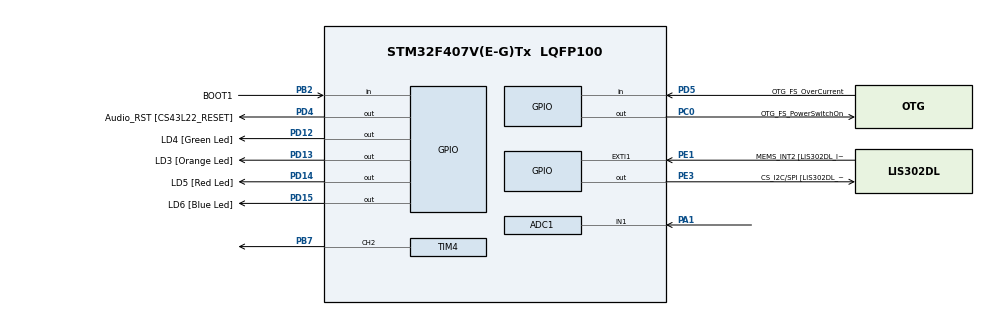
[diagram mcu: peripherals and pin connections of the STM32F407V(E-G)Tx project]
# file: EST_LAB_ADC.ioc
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ADC1.Channel-2\#ChannelRegularConversion=ADC_CHANNEL_1
ADC1.NbrOfConversionFlag=1
ADC1.Rank-2\#ChannelRegularConversion=1
ADC1.SamplingTime-2\#ChannelRegularConversion=ADC_SAMPLETIME_3CYCLES
ADC1.master=1
Mcu.Family=STM32F4
Mcu.Name=STM32F407V(E-G)Tx
Mcu.Package=LQFP100
NVIC.PriorityGroup=NVIC_PRIORITYGROUP_0
PA0-WKUP.Mode=SYS_WakeUp0
PA0-WKUP.Signal=SYS_WKUP
PA1.Signal=ADCx_IN1
PA10.GPIO_Label=OTG_FS_ID
PA10.GPIO_Mode=GPIO_MODE_AF_PP
PA10.GPIO_PuPd=GPIO_NOPULL
PA10.GPIO_Speed=GPIO_SPEED_FREQ_LOW
PA10.Signal=USB_OTG_FS_ID
PA11.GPIO_Label=OTG_FS_DM
PA11.GPIO_Mode=GPIO_MODE_AF_PP
PA11.GPIO_PuPd=GPIO_NOPULL
PA11.GPIO_Speed=GPIO_SPEED_FREQ_LOW
PA11.Signal=USB_OTG_FS_DM
PA12.GPIO_Label=OTG_FS_DP
PA12.GPIO_Mode=GPIO_MODE_AF_PP
PA12.GPIO_PuPd=GPIO_NOPULL
PA12.GPIO_Speed=GPIO_SPEED_FREQ_LOW
PA12.Signal=USB_OTG_FS_DP
PA13.GPIO_Label=SWDIO
PA13.Mode=Serial_Wire
PA13.Signal=SYS_JTMS-SWDIO
PA14.GPIO_Label=SWCLK
PA14.Mode=Serial_Wire
PA14.Signal=SYS_JTCK-SWCLK
PA4.GPIO_Label=I2S3_WS [CS43L22_LRCK]
PA4.GPIO_Mode=GPIO_MODE_AF_PP
PA4.GPIO_PuPd=GPIO_NOPULL
PA4.GPIO_Speed=GPIO_SPEED_FREQ_LOW
PA4.Signal=I2S3_WS
PA5.GPIO_Label=SPI1_SCK [LIS302DL_SCL/SPC]
PA5.GPIO_Mode=GPIO_MODE_AF_PP
PA5.GPIO_PuPd=GPIO_NOPULL
PA5.GPIO_Speed=GPIO_SPEED_FREQ_LOW
PA5.Signal=SPI1_SCK
PA6.GPIO_Label=SPI1_MISO [LIS302DL_SDO]
PA6.GPIO_Mode=GPIO_MODE_AF_PP
PA6.GPIO_PuPd=GPIO_NOPULL
PA6.GPIO_Speed=GPIO_SPEED_FREQ_LOW
PA6.Signal=SPI1_MISO
PA7.GPIO_Label=SPI1_MOSI [LIS302DL_SDA/SDI/SDO]
PA7.GPIO_Mode=GPIO_MODE_AF_PP
PA7.GPIO_PuPd=GPIO_NOPULL
PA7.GPIO_Speed=GPIO_SPEED_FREQ_LOW
PA7.Signal=SPI1_MOSI
PA9.GPIO_Label=VBUS_FS
PA9.GPIO_Mode=GPIO_MODE_INPUT
PA9.GPIO_PuPd=GPIO_NOPULL
PA9.Signal=USB_OTG_FS_VBUS
PB10.GPIO_Label=CLK_IN [MP45DT02_CLK]
PB10.GPIO_Mode=GPIO_MODE_AF_PP
PB10.GPIO_PuPd=GPIO_NOPULL
PB10.GPIO_Speed=GPIO_SPEED_FREQ_LOW
PB10.Signal=I2S2_CK
PB2.GPIO_Label=BOOT1
PB2.GPIO_Mode=GPIO_MODE_INPUT
PB2.GPIO_PuPd=GPIO_NOPULL
PB2.Signal=GPIO_Input
PB3.GPIO_Label=SWO
PB3.Signal=SYS_JTDO-SWO
PB6.GPIO_Label=Audio_SCL [CS43L22_SCL]
PB6.GPIO_Mode=GPIO_MODE_AF_OD
PB6.GPIO_PuPd=GPIO_NOPULL
PB6.GPIO_Speed=GPIO_SPEED_FREQ_LOW
PB6.Signal=I2C1_SCL
PB7.Signal=S_TIM4_CH2
PB9.GPIO_Label=Audio_SDA [CS43L22_SDA]
PB9.GPIO_Mode=GPIO_MODE_AF_OD
PB9.GPIO_PuPd=GPIO_NOPULL
PB9.GPIO_Speed=GPIO_SPEED_FREQ_LOW
PB9.Signal=I2C1_SDA
PC0.GPIO_Label=OTG_FS_PowerSwitchOn
PC0.GPIO_PuPd=GPIO_NOPULL
PC0.GPIO_Speed=GPIO_SPEED_FREQ_LOW
PC0.PinState=GPIO_PIN_SET
PC0.Signal=GPIO_Output
PC10.GPIO_Label=I2S3_SCK [CS43L22_SCLK]
PC10.GPIO_Mode=GPIO_MODE_AF_PP
PC10.GPIO_PuPd=GPIO_NOPULL
PC10.GPIO_Speed=GPIO_SPEED_FREQ_LOW
PC10.Signal=I2S3_CK
PC12.GPIO_Label=I2S3_SD [CS43L22_SDIN]
PC12.GPIO_Mode=GPIO_MODE_AF_PP
PC12.GPIO_PuPd=GPIO_NOPULL
PC12.GPIO_Speed=GPIO_SPEED_FREQ_LOW
PC12.Signal=I2S3_SD
PC14-OSC32_IN.GPIO_Label=PC14-OSC32_IN
PC14-OSC32_IN.Signal=RCC_OSC32_IN
PC15-OSC32_OUT.GPIO_Label=PC15-OSC32_OUT
PC15-OSC32_OUT.Signal=RCC_OSC32_OUT
PC3.GPIO_Label=PDM_OUT [MP45DT02_DOUT]
PC3.GPIO_Mode=GPIO_MODE_AF_PP
PC3.GPIO_PuPd=GPIO_NOPULL
PC3.GPIO_Speed=GPIO_SPEED_FREQ_LOW
PC3.Signal=I2S2_SD
PC7.GPIO_Label=I2S3_MCK [CS43L22_MCLK]
PC7.GPIO_Mode=GPIO_MODE_AF_PP
PC7.GPIO_PuPd=GPIO_NOPULL
PC7.GPIO_Speed=GPIO_SPEED_FREQ_LOW
PC7.Signal=I2S3_MCK
PD12.GPIO_Label=LD4 [Green Led]
PD12.GPIO_PuPd=GPIO_NOPULL
PD12.GPIO_Speed=GPIO_SPEED_FREQ_LOW
PD12.Signal=GPIO_Output
PD13.GPIO_Label=LD3 [Orange Led]
PD13.GPIO_PuPd=GPIO_NOPULL
PD13.GPIO_Speed=GPIO_SPEED_FREQ_LOW
PD13.Signal=GPIO_Output
PD14.GPIO_Label=LD5 [Red Led]
PD14.GPIO_PuPd=GPIO_NOPULL
PD14.GPIO_Speed=GPIO_SPEED_FREQ_LOW
PD14.Signal=GPIO_Output
PD15.GPIO_Label=LD6 [Blue Led]
PD15.GPIO_PuPd=GPIO_NOPULL
PD15.GPIO_Speed=GPIO_SPEED_FREQ_LOW
PD15.Signal=GPIO_Output
PD4.GPIO_Label=Audio_RST [CS43L22_RESET]
PD4.GPIO_PuPd=GPIO_NOPULL
PD4.GPIO_Speed=GPIO_SPEED_FREQ_LOW
PD4.Signal=GPIO_Output
PD5.GPIO_Label=OTG_FS_OverCurrent
PD5.GPIO_Mode=GPIO_MODE_INPUT
PD5.GPIO_PuPd=GPIO_NOPULL
PD5.Signal=GPIO_Input
PE1.GPIO_Label=MEMS_INT2 [LIS302DL_INT2]
PE1.GPIO_ModeDefaultEXTI=GPIO_MODE_EVT_RISING
PE1.GPIO_PuPd=GPIO_NOPULL
PE1.Signal=GPXTI1
PE3.GPIO_Label=CS_I2C/SPI [LIS302DL_CS_I2C/SPI]
PE3.GPIO_PuPd=GPIO_NOPULL
PE3.GPIO_Speed=GPIO_SPEED_FREQ_LOW
PE3.Signal=GPIO_Output
PH0-OSC_IN.GPIO_Label=PH0-OSC_IN
PH0-OSC_IN.Mode=HSE-External-Oscillator
PH0-OSC_IN.Signal=RCC_OSC_IN
PH1-OSC_OUT.GPIO_Label=PH1-OSC_OUT
PH1-OSC_OUT.Mode=HSE-External-Oscillator
PH1-OSC_OUT.Signal=RCC_OSC_OUT
ProjectManager.HeapSize=0x200
ProjectManager.StackSize=0x400
ProjectManager.TargetToolchain=STM32CubeIDE
RCC.48MHZClocksFreq_Value=20571428.57142857
RCC.AHBFreq_Value=72000000
RCC.APB1CLKDivider=RCC_HCLK_DIV2
RCC.APB1Freq_Value=36000000
RCC.APB1TimFreq_Value=72000000
RCC.APB2CLKDivider=RCC_HCLK_DIV2
RCC.APB2Freq_Value=36000000
RCC.APB2TimFreq_Value=72000000
RCC.CortexFreq_Value=72000000
RCC.HCLKFreq_Value=72000000
RCC.HSE_VALUE=8000000
RCC.HSI_VALUE=16000000
RCC.LSE_VALUE=32768
RCC.PLLM=4
RCC.PLLN=72
RCC.PLLQ=7
RCC.PLLSourceVirtual=RCC_PLLSOURCE_HSE
RCC.SYSCLKFreq_VALUE=72000000
RCC.SYSCLKSource=RCC_SYSCLKSOURCE_PLLCLK
RCC.VCOOutputFreq_Value=144000000
SH.ADCx_IN1.0=ADC1_IN1,IN1
SH.S_TIM4_CH2.0=TIM4_CH2,PWM Generation2 CH2
TIM4.Channel-PWM\ Generation2\ CH2=TIM_CHANNEL_2
VP_TIM4_VS_ClockSourceINT.Mode=Internal
board=STM32F407G-DISC1

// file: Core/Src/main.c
#include "main.h"

ADC_HandleTypeDef hadc1;
TIM_HandleTypeDef htim4;
uint16_t AD_RES = 0;

void SystemClock_Config(void);
static void MX_GPIO_Init(void);
static void MX_ADC1_Init(void);
static void MX_TIM4_Init(void);

int main(void)
{
  /* Reset of all peripherals, Initializes the Flash interface and the Systick. */
  HAL_Init();

  /* Configure the system clock */
  SystemClock_Config();

  /* Initialize all configured peripherals */
  MX_GPIO_Init();
  MX_ADC1_Init();
  MX_TIM4_Init();

  /* USER CODE BEGIN 2 */
  // Start PWM on Timer 4 Channel 1 (Connected to PD12 Green LED)
  HAL_TIM_PWM_Start(&htim4, TIM_CHANNEL_1);
  /* USER CODE END 2 */

  /* Infinite loop */
  while (1)
  {
    /* Trigger the ADC conversion in Interrupt Mode */
    HAL_ADC_Start_IT(&hadc1);

    /* Small delay for stability */
    HAL_Delay(10);
  }
}

static void MX_ADC1_Init(void)
{
  ADC_ChannelConfTypeDef sConfig = {0};

  hadc1.Instance = ADC1;
  hadc1.Init.ClockPrescaler = ADC_CLOCK_SYNC_PCLK_DIV4;
  hadc1.Init.Resolution = ADC_RESOLUTION_12B;
  hadc1.Init.ScanConvMode = DISABLE;
  hadc1.Init.ContinuousConvMode = DISABLE;
  hadc1.Init.DiscontinuousConvMode = DISABLE;
  hadc1.Init.ExternalTrigConvEdge = ADC_EXTERNALTRIGCONVEDGE_NONE;
  hadc1.Init.ExternalTrigConv = ADC_SOFTWARE_START;
  hadc1.Init.DataAlign = ADC_DATAALIGN_RIGHT;
  hadc1.Init.NbrOfConversion = 1;
  hadc1.Init.DMAContinuousRequests = DISABLE;
  hadc1.Init.EOCSelection = ADC_EOC_SINGLE_CONV;
  if (HAL_ADC_Init(&hadc1) != HAL_OK)
  {
    Error_Handler();
  }

  /** Configure Channel 1 (PA1)
  */
  sConfig.Channel = ADC_CHANNEL_1;
  sConfig.Rank = 1;
  sConfig.SamplingTime = ADC_SAMPLETIME_3CYCLES;
  if (HAL_ADC_ConfigChannel(&hadc1, &sConfig) != HAL_OK)
  {
    Error_Handler();
  }
}

static void MX_TIM4_Init(void)
{
  TIM_OC_InitTypeDef sConfigOC = {0};

  htim4.Instance = TIM4;
  htim4.Init.Prescaler = 0;
  htim4.Init.CounterMode = TIM_COUNTERMODE_UP;
  htim4.Init.Period = 65535; // 16-bit PWM range
  htim4.Init.ClockDivision = TIM_CLOCKDIVISION_DIV1;
  htim4.Init.AutoReloadPreload = TIM_AUTORELOAD_PRELOAD_ENABLE;
  if (HAL_TIM_PWM_Init(&htim4) != HAL_OK)
  {
    Error_Handler();
  }

  sConfigOC.OCMode = TIM_OCMODE_PWM1;
  sConfigOC.Pulse = 0;
  sConfigOC.OCPolarity = TIM_OCPOLARITY_HIGH;
  sConfigOC.OCFastMode = TIM_OCFAST_DISABLE;

  /* Configure Channel 1 for PD12 Green LED */
  if (HAL_TIM_PWM_ConfigChannel(&htim4, &sConfigOC, TIM_CHANNEL_1) != HAL_OK)
  {
    Error_Handler();
  }

  /* Link to GPIO hardware - Required for PWM pin functionality */
  HAL_TIM_MspPostInit(&htim4);
}

/**
  * @brief ADC Conversion Complete Callback
  * This runs automatically when ADC finishes reading PA1
  */
void HAL_ADC_ConvCpltCallback(ADC_HandleTypeDef* hadc)
{
    if(hadc->Instance == ADC1)
    {
        // Read 12-bit value
        AD_RES = HAL_ADC_GetValue(&hadc1);

        // Map 12-bit (4095) to 16-bit (65535) and update PWM
        TIM4->CCR1 = (AD_RES << 4);
    }
}

/**
  * @brief GPIO Initialization (Basic clocks and digital outputs)
  */
static void MX_GPIO_Init(void)
{
  __HAL_RCC_GPIOA_CLK_ENABLE();
  __HAL_RCC_GPIOD_CLK_ENABLE();

  /* Note: Pin PD12 is handled as Alternate Function by TIM4 initialization */
}

void SystemClock_Config(void)
{
  RCC_OscInitTypeDef RCC_OscInitStruct = {0};
  RCC_ClkInitTypeDef RCC_ClkInitStruct = {0};

  __HAL_RCC_PWR_CLK_ENABLE();
  __HAL_PWR_VOLTAGESCALING_CONFIG(PWR_REGULATOR_VOLTAGE_SCALE1);

  RCC_OscInitStruct.OscillatorType = RCC_OSCILLATORTYPE_HSE;
  RCC_OscInitStruct.HSEState = RCC_HSE_ON;
  RCC_OscInitStruct.PLL.PLLState = RCC_PLL_ON;
  RCC_OscInitStruct.PLL.PLLSource = RCC_PLLSOURCE_HSE;
  RCC_OscInitStruct.PLL.PLLM = 4;
  RCC_OscInitStruct.PLL.PLLN = 168;
  RCC_OscInitStruct.PLL.PLLP = RCC_PLLP_DIV2;
  RCC_OscInitStruct.PLL.PLLQ = 7;
  HAL_RCC_OscConfig(&RCC_OscInitStruct);

  RCC_ClkInitStruct.ClockType = RCC_CLOCKTYPE_HCLK|RCC_CLOCKTYPE_SYSCLK
                              |RCC_CLOCKTYPE_PCLK1|RCC_CLOCKTYPE_PCLK2;
  RCC_ClkInitStruct.SYSCLKSource = RCC_SYSCLKSOURCE_PLLCLK;
  RCC_ClkInitStruct.AHBCLKDivider = RCC_SYSCLK_DIV1;
  RCC_ClkInitStruct.APB1CLKDivider = RCC_HCLK_DIV4;
  RCC_ClkInitStruct.APB2CLKDivider = RCC_HCLK_DIV2;
  HAL_RCC_ClockConfig(&RCC_ClkInitStruct, FLASH_LATENCY_5);
}

void Error_Handler(void)
{
  __disable_irq();
  while (1);
}
